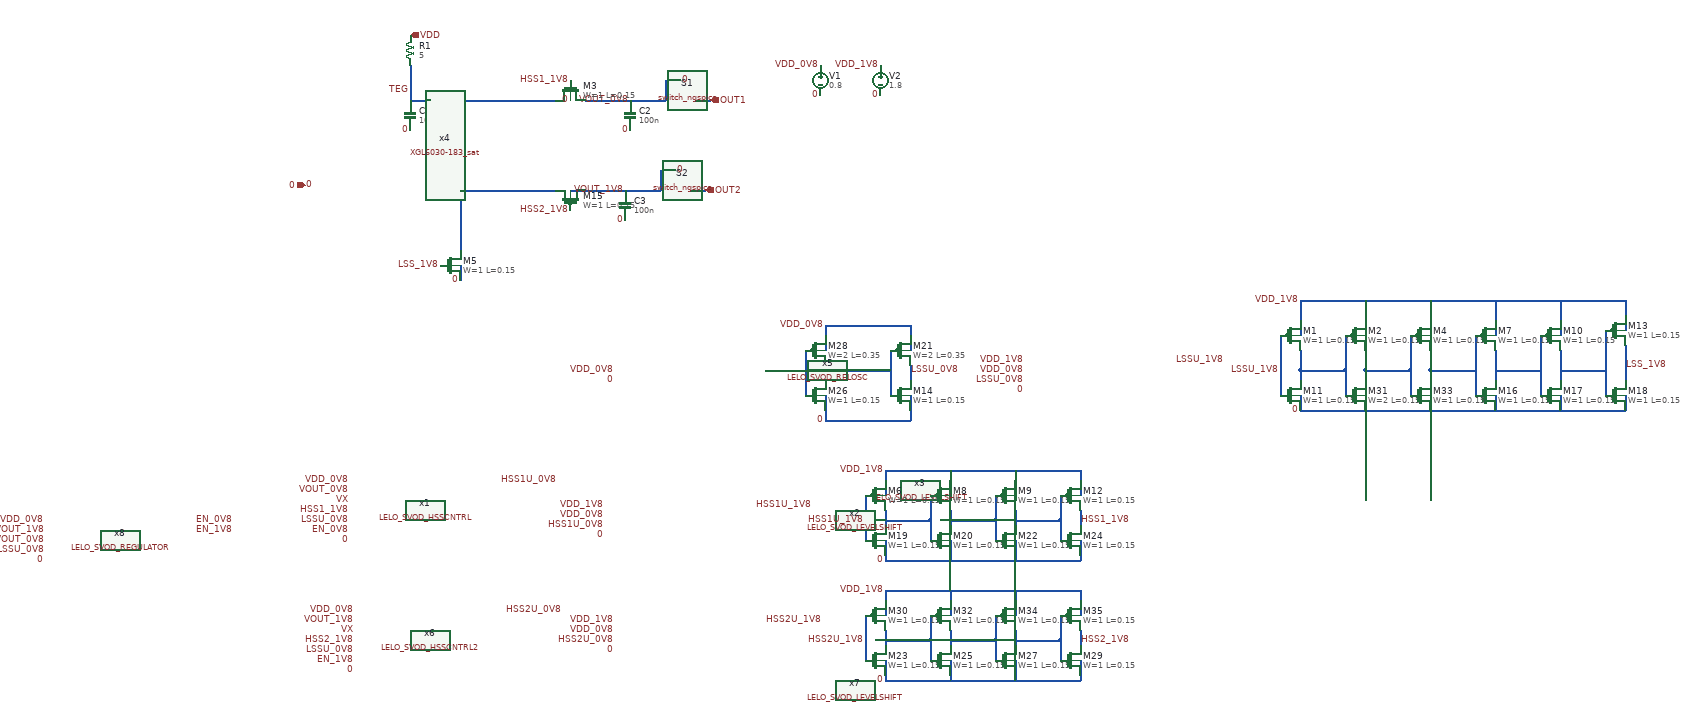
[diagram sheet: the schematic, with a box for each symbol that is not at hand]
v {xschem version=3.4.8RC file_version=1.2}
G {}
K {}
V {}
S {}
E {}
N -510 -330 -510 -260 {lab=TEG}
N -280 -260 -220 -260 {lab=VX}
N -410 -260 -280 -260 {lab=VX}
N -410 -260 -410 -100 {lab=VX}
N -490 -260 -470 -260 {lab=TEG}
N 1270 330 1270 360 {lab=0}
N 1660 240 1660 300 {lab=#net1}
N 1660 330 1660 360 {lab=0}
N 1620 210 1620 330 {lab=#net2}
N 1270 280 1360 280 {lab=#net3}
N -510 -260 -490 -260 {lab=TEG}
N 1790 240 1790 300 {lab=#net4}
N 1790 330 1790 360 {lab=0}
N 1750 210 1750 330 {lab=#net1}
N 1660 280 1750 280 {lab=#net1}
N 1920 230 1920 300 {lab=LSS_1V8}
N 1920 330 1920 360 {lab=0}
N 1880 200 1880 330 {lab=#net4}
N 1790 280 1880 280 {lab=#net4}
N -160 -260 -70 -260 {lab=VOUT_0V8}
N 1270 140 1850 140 {lab=VDD_1V8}
N 1660 140 1660 180 {lab=VDD_1V8}
N 1790 140 1790 180 {lab=VDD_1V8}
N 1920 140 1920 170 {lab=VDD_1V8}
N 1270 140 1270 180 {lab=VDD_1V8}
N 1270 240 1270 280 {lab=#net3}
N 1270 280 1270 300 {lab=#net3}
N 1230 210 1230 280 {lab=LSSU_1V8}
N 1230 280 1230 330 {lab=LSSU_1V8}
N 440 480 440 500 {lab=VDD_1V8}
N 570 480 570 500 {lab=VDD_1V8}
N 440 620 440 650 {lab=0}
N 570 620 570 650 {lab=0}
N 400 530 400 580 {lab=HSS1U_1V8}
N 400 580 400 620 {lab=HSS1U_1V8}
N 440 560 440 590 {lab=#net5}
N 440 650 440 660 {lab=0}
N 440 580 530 580 {lab=#net5}
N 530 530 530 580 {lab=#net5}
N 530 580 530 620 {lab=#net5}
N 570 560 570 590 {lab=#net6}
N 570 650 570 660 {lab=0}
N 700 480 700 500 {lab=VDD_1V8}
N 700 620 700 650 {lab=0}
N 570 580 660 580 {lab=#net6}
N 660 530 660 580 {lab=#net6}
N 660 580 660 620 {lab=#net6}
N 700 560 700 590 {lab=#net7}
N 700 650 700 660 {lab=0}
N 830 480 830 500 {lab=VDD_1V8}
N 830 620 830 650 {lab=0}
N 790 530 790 580 {lab=#net7}
N 790 580 790 620 {lab=#net7}
N 830 560 830 590 {lab=HSS1_1V8}
N 830 650 830 660 {lab=0}
N 1270 180 1270 210 {lab=VDD_1V8}
N 1660 180 1660 210 {lab=VDD_1V8}
N 1790 180 1790 210 {lab=VDD_1V8}
N 1920 170 1920 200 {lab=VDD_1V8}
N 440 500 440 530 {lab=VDD_1V8}
N 570 500 570 530 {lab=VDD_1V8}
N 700 500 700 530 {lab=VDD_1V8}
N 1400 330 1400 360 {lab=0}
N 1400 280 1490 280 {lab=#net8}
N 1400 140 1400 180 {lab=VDD_1V8}
N 1400 240 1400 280 {lab=#net8}
N 1400 280 1400 300 {lab=#net8}
N 1360 210 1360 280 {lab=#net3}
N 1360 280 1360 330 {lab=#net3}
N 1400 180 1400 210 {lab=VDD_1V8}
N 1530 330 1530 360 {lab=0}
N 1530 280 1620 280 {lab=#net2}
N 1530 140 1530 180 {lab=VDD_1V8}
N 1530 240 1530 280 {lab=#net2}
N 1530 280 1530 300 {lab=#net2}
N 1490 210 1490 280 {lab=#net8}
N 1490 280 1490 330 {lab=#net8}
N 1530 180 1530 210 {lab=VDD_1V8}
N 700 580 790 580 {lab=#net7}
N -410 -100 -410 -20 {lab=VX}
N -410 -20 -410 40 {lab=VX}
N -410 70 -410 100 {lab=0}
N 440 480 830 480 {lab=VDD_1V8}
N 830 500 830 530 {lab=VDD_1V8}
N 1850 140 1920 140 {lab=VDD_1V8}
N 1270 360 1920 360 {lab=0}
N 440 660 830 660 {lab=0}
N -70 -260 0 -260 {lab=VOUT_0V8}
N 0 -300 0 -260 {lab=VOUT_0V8}
N 0 -300 30 -300 {lab=VOUT_0V8}
N 60 -260 90 -260 {lab=OUT1}
N 450 240 450 330 {lab=#net9}
N 490 270 490 300 {lab=LSSU_0V8}
N 490 330 490 360 {lab=0}
N 490 210 490 240 {lab=VDD_0V8}
N 490 360 490 380 {lab=0}
N 490 190 490 210 {lab=VDD_0V8}
N 320 270 320 300 {lab=#net9}
N 280 240 280 330 {lab=#net10}
N 320 330 320 360 {lab=0}
N 320 210 320 240 {lab=VDD_0V8}
N 320 360 320 380 {lab=0}
N 320 190 320 210 {lab=VDD_0V8}
N 320 190 490 190 {lab=VDD_0V8}
N 320 380 490 380 {lab=0}
N 200 280 280 280 {lab=#net10}
N 320 280 450 280 {lab=#net9}
N -410 -80 -220 -80 {lab=VX}
N -190 -80 -160 -80 {lab=VOUT_1V8}
N -160 -80 -80 -80 {lab=VOUT_1V8}
N -80 -80 -10 -80 {lab=VOUT_1V8}
N 440 720 440 740 {lab=VDD_1V8}
N 570 720 570 740 {lab=VDD_1V8}
N 440 860 440 890 {lab=0}
N 570 860 570 890 {lab=0}
N 400 770 400 820 {lab=HSS2U_1V8}
N 400 820 400 860 {lab=HSS2U_1V8}
N 440 800 440 830 {lab=#net11}
N 440 890 440 900 {lab=0}
N 440 820 530 820 {lab=#net11}
N 530 770 530 820 {lab=#net11}
N 530 820 530 860 {lab=#net11}
N 570 800 570 830 {lab=#net12}
N 570 890 570 900 {lab=0}
N 700 720 700 740 {lab=VDD_1V8}
N 700 860 700 890 {lab=0}
N 570 820 660 820 {lab=#net12}
N 660 770 660 820 {lab=#net12}
N 660 820 660 860 {lab=#net12}
N 700 800 700 830 {lab=#net13}
N 700 890 700 900 {lab=0}
N 830 720 830 740 {lab=VDD_1V8}
N 830 860 830 890 {lab=0}
N 790 770 790 820 {lab=#net13}
N 790 820 790 860 {lab=#net13}
N 830 800 830 830 {lab=HSS2_1V8}
N 830 890 830 900 {lab=0}
N 440 740 440 770 {lab=VDD_1V8}
N 570 740 570 770 {lab=VDD_1V8}
N 700 740 700 770 {lab=VDD_1V8}
N 700 820 790 820 {lab=#net13}
N 440 720 830 720 {lab=VDD_1V8}
N 830 740 830 770 {lab=VDD_1V8}
N 440 900 830 900 {lab=0}
N -10 -120 -10 -80 {lab=VOUT_1V8}
N -10 -120 20 -120 {lab=VOUT_1V8}
N 50 -80 80 -80 {lab=VOUT_1V8}
C {devices/ipin.sym} -510 -390 0 1 {name=p2 lab=VDD}
C {devices/lab_pin.sym} -410 -260 3 1 {name=p3 sig_type=std_logic lab=VX}
C {devices/res.sym} -510 -360 0 1 {name=R1
value=5
footprint=1206
device=resistor
m=1}
C {devices/lab_pin.sym} 440 660 3 0 {name=p77 sig_type=std_logic lab=0}
C {devices/lab_pin.sym} -100 300 3 0 {name=p13 sig_type=std_logic lab=0}
C {devices/lab_pin.sym} 1920 270 0 1 {name=p30 sig_type=std_logic lab=LSS_1V8}
C {devices/capa.sym} -510 -230 0 1 {name=C1
m=1
value=100u
footprint=1206
device="ceramic capacitor"}
C {devices/lab_pin.sym} -510 -200 3 0 {name=p7 sig_type=std_logic lab=0}
C {sky130_fd_pr/nfet_01v8_lvt.sym} -430 70 0 0 {name=M5
W=1
L=0.15
nf=1
mult=15804
ad="expr('int((@nf + 1)/2) * @W / @nf * 0.29')"
pd="expr('2*int((@nf + 1)/2) * (@W / @nf + 0.29)')"
as="expr('int((@nf + 2)/2) * @W / @nf * 0.29')"
ps="expr('2*int((@nf + 2)/2) * (@W / @nf + 0.29)')"
nrd="expr('0.29 / @W ')" nrs="expr('0.29 / @W ')"
sa=0 sb=0 sd=0
model=nfet_01v8_lvt
spiceprefix=X
}
C {devices/lab_pin.sym} -510 -280 2 1 {name=p93 sig_type=std_logic lab=TEG}
C {devices/capa.sym} -70 -230 0 1 {name=C2
m=1
value=100n
footprint=1206
device="ceramic capacitor"}
C {devices/lab_pin.sym} -70 -200 3 0 {name=p1 sig_type=std_logic lab=0}
C {devices/lab_pin.sym} -70 -260 1 0 {name=p35 sig_type=std_logic lab=VOUT_0V8}
C {sky130_fd_pr/nfet_01v8.sym} 1250 330 0 0 {name=M11
W=1
L=0.15
nf=1 
mult=1
ad="expr('int((@nf + 1)/2) * @W / @nf * 0.29')"
pd="expr('2*int((@nf + 1)/2) * (@W / @nf + 0.29)')"
as="expr('int((@nf + 2)/2) * @W / @nf * 0.29')"
ps="expr('2*int((@nf + 2)/2) * (@W / @nf + 0.29)')"
nrd="expr('0.29 / @W ')" nrs="expr('0.29 / @W ')"
sa=0 sb=0 sd=0
model=nfet_01v8
spiceprefix=X
}
C {sky130_fd_pr/nfet_01v8.sym} 1640 330 0 0 {name=M16
W=1
L=0.15
nf=1 
mult=27
ad="expr('int((@nf + 1)/2) * @W / @nf * 0.29')"
pd="expr('2*int((@nf + 1)/2) * (@W / @nf + 0.29)')"
as="expr('int((@nf + 2)/2) * @W / @nf * 0.29')"
ps="expr('2*int((@nf + 2)/2) * (@W / @nf + 0.29)')"
nrd="expr('0.29 / @W ')" nrs="expr('0.29 / @W ')"
sa=0 sb=0 sd=0
model=nfet_01v8
spiceprefix=X
}
C {sky130_fd_pr/nfet_01v8.sym} 1770 330 0 0 {name=M17
W=1
L=0.15
nf=1 
mult=81
ad="expr('int((@nf + 1)/2) * @W / @nf * 0.29')"
pd="expr('2*int((@nf + 1)/2) * (@W / @nf + 0.29)')"
as="expr('int((@nf + 2)/2) * @W / @nf * 0.29')"
ps="expr('2*int((@nf + 2)/2) * (@W / @nf + 0.29)')"
nrd="expr('0.29 / @W ')" nrs="expr('0.29 / @W ')"
sa=0 sb=0 sd=0
model=nfet_01v8
spiceprefix=X
}
C {sky130_fd_pr/nfet_01v8.sym} 1900 330 0 0 {name=M18
W=1
L=0.15
nf=1 
mult=243
ad="expr('int((@nf + 1)/2) * @W / @nf * 0.29')"
pd="expr('2*int((@nf + 1)/2) * (@W / @nf + 0.29)')"
as="expr('int((@nf + 2)/2) * @W / @nf * 0.29')"
ps="expr('2*int((@nf + 2)/2) * (@W / @nf + 0.29)')"
nrd="expr('0.29 / @W ')" nrs="expr('0.29 / @W ')"
sa=0 sb=0 sd=0
model=nfet_01v8
spiceprefix=X
}
C {sky130_fd_pr/nfet_01v8.sym} 420 620 0 0 {name=M19
W=1
L=0.15
nf=1 
mult=1
ad="expr('int((@nf + 1)/2) * @W / @nf * 0.29')"
pd="expr('2*int((@nf + 1)/2) * (@W / @nf + 0.29)')"
as="expr('int((@nf + 2)/2) * @W / @nf * 0.29')"
ps="expr('2*int((@nf + 2)/2) * (@W / @nf + 0.29)')"
nrd="expr('0.29 / @W ')" nrs="expr('0.29 / @W ')"
sa=0 sb=0 sd=0
model=nfet_01v8
spiceprefix=X
}
C {sky130_fd_pr/nfet_01v8.sym} 550 620 0 0 {name=M20
W=1
L=0.15
nf=1 
mult=3
ad="expr('int((@nf + 1)/2) * @W / @nf * 0.29')"
pd="expr('2*int((@nf + 1)/2) * (@W / @nf + 0.29)')"
as="expr('int((@nf + 2)/2) * @W / @nf * 0.29')"
ps="expr('2*int((@nf + 2)/2) * (@W / @nf + 0.29)')"
nrd="expr('0.29 / @W ')" nrs="expr('0.29 / @W ')"
sa=0 sb=0 sd=0
model=nfet_01v8
spiceprefix=X
}
C {sky130_fd_pr/nfet_01v8.sym} 680 620 0 0 {name=M22
W=1
L=0.15
nf=1 
mult=9
ad="expr('int((@nf + 1)/2) * @W / @nf * 0.29')"
pd="expr('2*int((@nf + 1)/2) * (@W / @nf + 0.29)')"
as="expr('int((@nf + 2)/2) * @W / @nf * 0.29')"
ps="expr('2*int((@nf + 2)/2) * (@W / @nf + 0.29)')"
nrd="expr('0.29 / @W ')" nrs="expr('0.29 / @W ')"
sa=0 sb=0 sd=0
model=nfet_01v8
spiceprefix=X
}
C {sky130_fd_pr/nfet_01v8.sym} 810 620 0 0 {name=M24
W=1
L=0.15
nf=1 
mult=27
ad="expr('int((@nf + 1)/2) * @W / @nf * 0.29')"
pd="expr('2*int((@nf + 1)/2) * (@W / @nf + 0.29)')"
as="expr('int((@nf + 2)/2) * @W / @nf * 0.29')"
ps="expr('2*int((@nf + 2)/2) * (@W / @nf + 0.29)')"
nrd="expr('0.29 / @W ')" nrs="expr('0.29 / @W ')"
sa=0 sb=0 sd=0
model=nfet_01v8
spiceprefix=X
}
C {sky130_fd_pr/nfet_01v8.sym} 1380 330 0 0 {name=M31
W=2
L=0.15
nf=1 
mult=3
ad="expr('int((@nf + 1)/2) * @W / @nf * 0.29')"
pd="expr('2*int((@nf + 1)/2) * (@W / @nf + 0.29)')"
as="expr('int((@nf + 2)/2) * @W / @nf * 0.29')"
ps="expr('2*int((@nf + 2)/2) * (@W / @nf + 0.29)')"
nrd="expr('0.29 / @W ')" nrs="expr('0.29 / @W ')"
sa=0 sb=0 sd=0
model=nfet_01v8
spiceprefix=X
}
C {sky130_fd_pr/nfet_01v8.sym} 1510 330 0 0 {name=M33
W=1
L=0.15
nf=1 
mult=9
ad="expr('int((@nf + 1)/2) * @W / @nf * 0.29')"
pd="expr('2*int((@nf + 1)/2) * (@W / @nf + 0.29)')"
as="expr('int((@nf + 2)/2) * @W / @nf * 0.29')"
ps="expr('2*int((@nf + 2)/2) * (@W / @nf + 0.29)')"
nrd="expr('0.29 / @W ')" nrs="expr('0.29 / @W ')"
sa=0 sb=0 sd=0
model=nfet_01v8
spiceprefix=X
}
C {devices/lab_pin.sym} -190 -300 1 0 {name=p101 sig_type=std_logic lab=HSS1_1V8}
C {sky130_fd_pr/nfet_01v8_lvt.sym} -190 -280 1 0 {name=M3
W=1
L=0.15
nf=1
mult=3244
ad="expr('int((@nf + 1)/2) * @W / @nf * 0.29')"
pd="expr('2*int((@nf + 1)/2) * (@W / @nf + 0.29)')"
as="expr('int((@nf + 2)/2) * @W / @nf * 0.29')"
ps="expr('2*int((@nf + 2)/2) * (@W / @nf + 0.29)')"
nrd="expr('0.29 / @W ')" nrs="expr('0.29 / @W ')"
sa=0 sb=0 sd=0
model=nfet_01v8_lvt
spiceprefix=X
}
C {devices/lab_pin.sym} 490 280 0 1 {name=p10 sig_type=std_logic lab=LSSU_0V8}
C {devices/lab_pin.sym} -410 100 3 0 {name=p12 sig_type=std_logic lab=0}
C {LELO_SVOD_SKY130A/LELO_SVOD_HSSCNTRL.sym} -480 560 0 0 {name=x1}
C {devices/lab_pin.sym} -630 620 0 0 {name=p19 sig_type=std_logic lab=0}
C {devices/lab_pin.sym} -330 500 2 0 {name=p22 sig_type=std_logic lab=HSS1U_0V8}
C {devices/lab_pin.sym} -630 540 2 1 {name=p26 sig_type=std_logic lab=VX}
C {devices/lab_pin.sym} -630 520 0 0 {name=p27 sig_type=std_logic lab=VOUT_0V8}
C {devices/lab_pin.sym} -190 -260 3 0 {name=p6 sig_type=std_logic lab=0}
C {LELO_SVOD_SKY130A/LELO_SVOD_LEVELSHIFT.sym} 30 580 0 0 {name=x2}
C {LELO_SVOD_SKY130A/LELO_SVOD_LEVELSHIFT.sym} 870 290 0 0 {name=x3}
C {devices/lab_pin.sym} 180 550 2 0 {name=p8 sig_type=std_logic lab=HSS1U_1V8}
C {devices/lab_pin.sym} -120 610 0 0 {name=p20 sig_type=std_logic lab=0}
C {devices/lab_pin.sym} 1020 260 0 1 {name=p23 sig_type=std_logic lab=LSSU_1V8}
C {devices/lab_pin.sym} 720 320 0 0 {name=p24 sig_type=std_logic lab=0}
C {sky130_fd_pr/pfet_01v8_hvt.sym} 420 530 0 0 {name=M6
W=1
L=0.15
nf=1
mult=1
ad="expr('int((@nf + 1)/2) * @W / @nf * 0.29')"
pd="expr('2*int((@nf + 1)/2) * (@W / @nf + 0.29)')"
as="expr('int((@nf + 2)/2) * @W / @nf * 0.29')"
ps="expr('2*int((@nf + 2)/2) * (@W / @nf + 0.29)')"
nrd="expr('0.29 / @W ')" nrs="expr('0.29 / @W ')"
sa=0 sb=0 sd=0
model=pfet_01v8_hvt
spiceprefix=X
}
C {sky130_fd_pr/pfet_01v8_hvt.sym} 550 530 0 0 {name=M8
W=1
L=0.15
nf=1
mult=3
ad="expr('int((@nf + 1)/2) * @W / @nf * 0.29')"
pd="expr('2*int((@nf + 1)/2) * (@W / @nf + 0.29)')"
as="expr('int((@nf + 2)/2) * @W / @nf * 0.29')"
ps="expr('2*int((@nf + 2)/2) * (@W / @nf + 0.29)')"
nrd="expr('0.29 / @W ')" nrs="expr('0.29 / @W ')"
sa=0 sb=0 sd=0
model=pfet_01v8_hvt
spiceprefix=X
}
C {sky130_fd_pr/pfet_01v8_hvt.sym} 680 530 0 0 {name=M9
W=1
L=0.15
nf=1
mult=9
ad="expr('int((@nf + 1)/2) * @W / @nf * 0.29')"
pd="expr('2*int((@nf + 1)/2) * (@W / @nf + 0.29)')"
as="expr('int((@nf + 2)/2) * @W / @nf * 0.29')"
ps="expr('2*int((@nf + 2)/2) * (@W / @nf + 0.29)')"
nrd="expr('0.29 / @W ')" nrs="expr('0.29 / @W ')"
sa=0 sb=0 sd=0
model=pfet_01v8_hvt
spiceprefix=X
}
C {sky130_fd_pr/pfet_01v8_hvt.sym} 810 530 0 0 {name=M12
W=1
L=0.15
nf=1
mult=27
ad="expr('int((@nf + 1)/2) * @W / @nf * 0.29')"
pd="expr('2*int((@nf + 1)/2) * (@W / @nf + 0.29)')"
as="expr('int((@nf + 2)/2) * @W / @nf * 0.29')"
ps="expr('2*int((@nf + 2)/2) * (@W / @nf + 0.29)')"
nrd="expr('0.29 / @W ')" nrs="expr('0.29 / @W ')"
sa=0 sb=0 sd=0
model=pfet_01v8_hvt
spiceprefix=X
}
C {sky130_fd_pr/pfet_01v8_hvt.sym} 1250 210 0 0 {name=M1
W=1
L=0.15
nf=1
mult=1
ad="expr('int((@nf + 1)/2) * @W / @nf * 0.29')"
pd="expr('2*int((@nf + 1)/2) * (@W / @nf + 0.29)')"
as="expr('int((@nf + 2)/2) * @W / @nf * 0.29')"
ps="expr('2*int((@nf + 2)/2) * (@W / @nf + 0.29)')"
nrd="expr('0.29 / @W ')" nrs="expr('0.29 / @W ')"
sa=0 sb=0 sd=0
model=pfet_01v8_hvt
spiceprefix=X
}
C {sky130_fd_pr/pfet_01v8_hvt.sym} 1380 210 0 0 {name=M2
W=1
L=0.15
nf=1
mult=3
ad="expr('int((@nf + 1)/2) * @W / @nf * 0.29')"
pd="expr('2*int((@nf + 1)/2) * (@W / @nf + 0.29)')"
as="expr('int((@nf + 2)/2) * @W / @nf * 0.29')"
ps="expr('2*int((@nf + 2)/2) * (@W / @nf + 0.29)')"
nrd="expr('0.29 / @W ')" nrs="expr('0.29 / @W ')"
sa=0 sb=0 sd=0
model=pfet_01v8_hvt
spiceprefix=X
}
C {sky130_fd_pr/pfet_01v8_hvt.sym} 1510 210 0 0 {name=M4
W=1
L=0.15
nf=1
mult=9
ad="expr('int((@nf + 1)/2) * @W / @nf * 0.29')"
pd="expr('2*int((@nf + 1)/2) * (@W / @nf + 0.29)')"
as="expr('int((@nf + 2)/2) * @W / @nf * 0.29')"
ps="expr('2*int((@nf + 2)/2) * (@W / @nf + 0.29)')"
nrd="expr('0.29 / @W ')" nrs="expr('0.29 / @W ')"
sa=0 sb=0 sd=0
model=pfet_01v8_hvt
spiceprefix=X
}
C {sky130_fd_pr/pfet_01v8_hvt.sym} 1640 210 0 0 {name=M7
W=1
L=0.15
nf=1
mult=27
ad="expr('int((@nf + 1)/2) * @W / @nf * 0.29')"
pd="expr('2*int((@nf + 1)/2) * (@W / @nf + 0.29)')"
as="expr('int((@nf + 2)/2) * @W / @nf * 0.29')"
ps="expr('2*int((@nf + 2)/2) * (@W / @nf + 0.29)')"
nrd="expr('0.29 / @W ')" nrs="expr('0.29 / @W ')"
sa=0 sb=0 sd=0
model=pfet_01v8_hvt
spiceprefix=X
}
C {sky130_fd_pr/pfet_01v8_hvt.sym} 1770 210 0 0 {name=M10
W=1
L=0.15
nf=1
mult=81
ad="expr('int((@nf + 1)/2) * @W / @nf * 0.29')"
pd="expr('2*int((@nf + 1)/2) * (@W / @nf + 0.29)')"
as="expr('int((@nf + 2)/2) * @W / @nf * 0.29')"
ps="expr('2*int((@nf + 2)/2) * (@W / @nf + 0.29)')"
nrd="expr('0.29 / @W ')" nrs="expr('0.29 / @W ')"
sa=0 sb=0 sd=0
model=pfet_01v8_hvt
spiceprefix=X
}
C {sky130_fd_pr/pfet_01v8_hvt.sym} 1900 200 0 0 {name=M13
W=1
L=0.15
nf=1
mult=243
ad="expr('int((@nf + 1)/2) * @W / @nf * 0.29')"
pd="expr('2*int((@nf + 1)/2) * (@W / @nf + 0.29)')"
as="expr('int((@nf + 2)/2) * @W / @nf * 0.29')"
ps="expr('2*int((@nf + 2)/2) * (@W / @nf + 0.29)')"
nrd="expr('0.29 / @W ')" nrs="expr('0.29 / @W ')"
sa=0 sb=0 sd=0
model=pfet_01v8_hvt
spiceprefix=X
}
C {devices/lab_pin.sym} -120 590 2 1 {name=p5 sig_type=std_logic lab=HSS1U_0V8}
C {devices/lab_pin.sym} 400 580 2 1 {name=p9 sig_type=std_logic lab=HSS1U_1V8}
C {devices/lab_pin.sym} 1270 360 3 0 {name=p4 sig_type=std_logic lab=0}
C {devices/vsource.sym} 310 -300 0 0 {name=V1 value=0.8 savecurrent=false}
C {devices/vsource.sym} 430 -300 0 0 {name=V2 value=1.8 savecurrent=false}
C {devices/lab_pin.sym} 310 -270 3 0 {name=p11 sig_type=std_logic lab=0}
C {devices/lab_pin.sym} 430 -270 3 0 {name=p14 sig_type=std_logic lab=0}
C {devices/lab_pin.sym} 310 -330 1 0 {name=p15 sig_type=std_logic lab=VDD_0V8}
C {devices/lab_pin.sym} 430 -330 1 0 {name=p16 sig_type=std_logic lab=VDD_1V8}
C {devices/lab_pin.sym} -100 280 0 0 {name=p17 sig_type=std_logic lab=VDD_0V8}
C {devices/lab_pin.sym} -630 500 0 0 {name=p21 sig_type=std_logic lab=VDD_0V8}
C {devices/lab_pin.sym} -120 570 0 0 {name=p28 sig_type=std_logic lab=VDD_0V8}
C {devices/lab_pin.sym} 720 280 0 0 {name=p29 sig_type=std_logic lab=VDD_0V8}
C {devices/lab_pin.sym} -120 550 0 0 {name=p31 sig_type=std_logic lab=VDD_1V8}
C {devices/lab_pin.sym} 720 260 0 0 {name=p32 sig_type=std_logic lab=VDD_1V8}
C {devices/lab_pin.sym} 440 480 0 0 {name=p33 sig_type=std_logic lab=VDD_1V8}
C {devices/lab_pin.sym} 1270 140 0 0 {name=p34 sig_type=std_logic lab=VDD_1V8}
C {devices/lab_pin.sym} -450 70 0 0 {name=p36 sig_type=std_logic lab=LSS_1V8}
C {devices/lab_pin.sym} 720 300 0 0 {name=p37 sig_type=std_logic lab=LSSU_0V8}
C {devices/lab_pin.sym} 1230 280 0 0 {name=p38 sig_type=std_logic lab=LSSU_1V8}
C {devices/lab_pin.sym} 830 580 2 0 {name=p39 sig_type=std_logic lab=HSS1_1V8}
C {devices/ipin.sym} -720 -90 0 0 {name=p40 lab=0}
C {devices/lab_pin.sym} -720 -90 2 0 {name=p41 sig_type=std_logic lab=0}
C {devices/switch_ngspice.sym} 30 -260 3 1 {name=S1 model=SW1
device_model=".MODEL SW1 SW 
+ VT=0.7 VH=0.001
+ RON=0.001 ROFF=10G "}
C {devices/lab_pin.sym} 50 -300 1 0 {name=p42 sig_type=std_logic lab=0}
C {devices/lab_pin.sym} -630 580 0 0 {name=p25 sig_type=std_logic lab=LSSU_0V8}
C {sky130_fd_pr/nfet_01v8_lvt.sym} 470 330 0 0 {name=M14
W=1
L=0.15
nf=1
mult=2
ad="expr('int((@nf + 1)/2) * @W / @nf * 0.29')"
pd="expr('2*int((@nf + 1)/2) * (@W / @nf + 0.29)')"
as="expr('int((@nf + 2)/2) * @W / @nf * 0.29')"
ps="expr('2*int((@nf + 2)/2) * (@W / @nf + 0.29)')"
nrd="expr('0.29 / @W ')" nrs="expr('0.29 / @W ')"
sa=0 sb=0 sd=0
model=nfet_01v8_lvt
spiceprefix=X
}
C {sky130_fd_pr/pfet_01v8_lvt.sym} 470 240 0 0 {name=M21
W=2
L=0.35
nf=1
mult=4
ad="expr('int((@nf + 1)/2) * @W / @nf * 0.29')"
pd="expr('2*int((@nf + 1)/2) * (@W / @nf + 0.29)')"
as="expr('int((@nf + 2)/2) * @W / @nf * 0.29')"
ps="expr('2*int((@nf + 2)/2) * (@W / @nf + 0.29)')"
nrd="expr('0.29 / @W ')" nrs="expr('0.29 / @W ')"
sa=0 sb=0 sd=0
model=pfet_01v8_lvt
spiceprefix=X
}
C {devices/lab_pin.sym} -630 560 0 0 {name=p49 sig_type=std_logic lab=HSS1_1V8}
C {sky130_fd_pr/nfet_01v8_lvt.sym} 300 330 0 0 {name=M26
W=1
L=0.15
nf=1
mult=1
ad="expr('int((@nf + 1)/2) * @W / @nf * 0.29')"
pd="expr('2*int((@nf + 1)/2) * (@W / @nf + 0.29)')"
as="expr('int((@nf + 2)/2) * @W / @nf * 0.29')"
ps="expr('2*int((@nf + 2)/2) * (@W / @nf + 0.29)')"
nrd="expr('0.29 / @W ')" nrs="expr('0.29 / @W ')"
sa=0 sb=0 sd=0
model=nfet_01v8_lvt
spiceprefix=X
}
C {sky130_fd_pr/pfet_01v8_lvt.sym} 300 240 0 0 {name=M28
W=2
L=0.35
nf=1
mult=1
ad="expr('int((@nf + 1)/2) * @W / @nf * 0.29')"
pd="expr('2*int((@nf + 1)/2) * (@W / @nf + 0.29)')"
as="expr('int((@nf + 2)/2) * @W / @nf * 0.29')"
ps="expr('2*int((@nf + 2)/2) * (@W / @nf + 0.29)')"
nrd="expr('0.29 / @W ')" nrs="expr('0.29 / @W ')"
sa=0 sb=0 sd=0
model=pfet_01v8_lvt
spiceprefix=X
}
C {devices/lab_pin.sym} 320 190 1 0 {name=p51 sig_type=std_logic lab=VDD_0V8}
C {devices/lab_pin.sym} 320 380 3 0 {name=p52 sig_type=std_logic lab=0}
C {LELO_SVOD_SKY130A/XGL6030-183_sat.sym} -440 -260 1 0 {name=x4}
C {LELO_SVOD_SKY130A/LELO_SVOD_RELOSC.sym} 50 290 0 0 {name=x5}
C {sky130_fd_pr/pfet_01v8.sym} -190 -60 1 1 {name=M15
W=1
L=0.15
nf=1
mult=481
ad="expr('int((@nf + 1)/2) * @W / @nf * 0.29')"
pd="expr('2*int((@nf + 1)/2) * (@W / @nf + 0.29)')"
as="expr('int((@nf + 2)/2) * @W / @nf * 0.29')"
ps="expr('2*int((@nf + 2)/2) * (@W / @nf + 0.29)')"
nrd="expr('0.29 / @W ')" nrs="expr('0.29 / @W ')"
sa=0 sb=0 sd=0
model=pfet_01v8
spiceprefix=X
}
C {devices/capa.sym} -80 -50 0 1 {name=C3
m=1
value=100n
footprint=1206
device="ceramic capacitor"}
C {devices/lab_pin.sym} -80 -20 3 0 {name=p44 sig_type=std_logic lab=0}
C {devices/lab_pin.sym} -80 -80 1 0 {name=p45 sig_type=std_logic lab=VOUT_1V8}
C {devices/opin.sym} 80 -80 0 0 {name=p47 lab=OUT2}
C {LELO_SVOD_SKY130A/LELO_SVOD_HSSCNTRL2.sym} -470 820 0 0 {name=x6}
C {devices/lab_pin.sym} -620 800 2 1 {name=p48 sig_type=std_logic lab=VX}
C {devices/lab_pin.sym} -620 760 0 0 {name=p50 sig_type=std_logic lab=VDD_0V8}
C {devices/lab_pin.sym} -620 780 0 0 {name=p53 sig_type=std_logic lab=VOUT_1V8}
C {devices/lab_pin.sym} -620 840 0 0 {name=p54 sig_type=std_logic lab=LSSU_0V8}
C {devices/lab_pin.sym} -620 880 0 0 {name=p56 sig_type=std_logic lab=0}
C {devices/lab_pin.sym} -320 760 2 0 {name=p57 sig_type=std_logic lab=HSS2U_0V8}
C {LELO_SVOD_SKY130A/LELO_SVOD_LEVELSHIFT.sym} 50 810 0 0 {name=x7}
C {devices/lab_pin.sym} 200 780 2 0 {name=p58 sig_type=std_logic lab=HSS2U_1V8}
C {devices/lab_pin.sym} -100 840 0 0 {name=p59 sig_type=std_logic lab=0}
C {devices/lab_pin.sym} -100 800 0 0 {name=p61 sig_type=std_logic lab=VDD_0V8}
C {devices/lab_pin.sym} -100 780 0 0 {name=p62 sig_type=std_logic lab=VDD_1V8}
C {devices/lab_pin.sym} -100 820 2 1 {name=p60 sig_type=std_logic lab=HSS2U_0V8}
C {devices/lab_pin.sym} 440 900 3 0 {name=p63 sig_type=std_logic lab=0}
C {sky130_fd_pr/nfet_01v8.sym} 420 860 0 0 {name=M23
W=1
L=0.15
nf=1 
mult=1
ad="expr('int((@nf + 1)/2) * @W / @nf * 0.29')"
pd="expr('2*int((@nf + 1)/2) * (@W / @nf + 0.29)')"
as="expr('int((@nf + 2)/2) * @W / @nf * 0.29')"
ps="expr('2*int((@nf + 2)/2) * (@W / @nf + 0.29)')"
nrd="expr('0.29 / @W ')" nrs="expr('0.29 / @W ')"
sa=0 sb=0 sd=0
model=nfet_01v8
spiceprefix=X
}
C {sky130_fd_pr/nfet_01v8.sym} 550 860 0 0 {name=M25
W=1
L=0.15
nf=1 
mult=3
ad="expr('int((@nf + 1)/2) * @W / @nf * 0.29')"
pd="expr('2*int((@nf + 1)/2) * (@W / @nf + 0.29)')"
as="expr('int((@nf + 2)/2) * @W / @nf * 0.29')"
ps="expr('2*int((@nf + 2)/2) * (@W / @nf + 0.29)')"
nrd="expr('0.29 / @W ')" nrs="expr('0.29 / @W ')"
sa=0 sb=0 sd=0
model=nfet_01v8
spiceprefix=X
}
C {sky130_fd_pr/nfet_01v8.sym} 680 860 0 0 {name=M27
W=1
L=0.15
nf=1 
mult=9
ad="expr('int((@nf + 1)/2) * @W / @nf * 0.29')"
pd="expr('2*int((@nf + 1)/2) * (@W / @nf + 0.29)')"
as="expr('int((@nf + 2)/2) * @W / @nf * 0.29')"
ps="expr('2*int((@nf + 2)/2) * (@W / @nf + 0.29)')"
nrd="expr('0.29 / @W ')" nrs="expr('0.29 / @W ')"
sa=0 sb=0 sd=0
model=nfet_01v8
spiceprefix=X
}
C {sky130_fd_pr/nfet_01v8.sym} 810 860 0 0 {name=M29
W=1
L=0.15
nf=1 
mult=27
ad="expr('int((@nf + 1)/2) * @W / @nf * 0.29')"
pd="expr('2*int((@nf + 1)/2) * (@W / @nf + 0.29)')"
as="expr('int((@nf + 2)/2) * @W / @nf * 0.29')"
ps="expr('2*int((@nf + 2)/2) * (@W / @nf + 0.29)')"
nrd="expr('0.29 / @W ')" nrs="expr('0.29 / @W ')"
sa=0 sb=0 sd=0
model=nfet_01v8
spiceprefix=X
}
C {sky130_fd_pr/pfet_01v8_hvt.sym} 420 770 0 0 {name=M30
W=1
L=0.15
nf=1
mult=1
ad="expr('int((@nf + 1)/2) * @W / @nf * 0.29')"
pd="expr('2*int((@nf + 1)/2) * (@W / @nf + 0.29)')"
as="expr('int((@nf + 2)/2) * @W / @nf * 0.29')"
ps="expr('2*int((@nf + 2)/2) * (@W / @nf + 0.29)')"
nrd="expr('0.29 / @W ')" nrs="expr('0.29 / @W ')"
sa=0 sb=0 sd=0
model=pfet_01v8_hvt
spiceprefix=X
}
C {sky130_fd_pr/pfet_01v8_hvt.sym} 550 770 0 0 {name=M32
W=1
L=0.15
nf=1
mult=3
ad="expr('int((@nf + 1)/2) * @W / @nf * 0.29')"
pd="expr('2*int((@nf + 1)/2) * (@W / @nf + 0.29)')"
as="expr('int((@nf + 2)/2) * @W / @nf * 0.29')"
ps="expr('2*int((@nf + 2)/2) * (@W / @nf + 0.29)')"
nrd="expr('0.29 / @W ')" nrs="expr('0.29 / @W ')"
sa=0 sb=0 sd=0
model=pfet_01v8_hvt
spiceprefix=X
}
C {sky130_fd_pr/pfet_01v8_hvt.sym} 680 770 0 0 {name=M34
W=1
L=0.15
nf=1
mult=9
ad="expr('int((@nf + 1)/2) * @W / @nf * 0.29')"
pd="expr('2*int((@nf + 1)/2) * (@W / @nf + 0.29)')"
as="expr('int((@nf + 2)/2) * @W / @nf * 0.29')"
ps="expr('2*int((@nf + 2)/2) * (@W / @nf + 0.29)')"
nrd="expr('0.29 / @W ')" nrs="expr('0.29 / @W ')"
sa=0 sb=0 sd=0
model=pfet_01v8_hvt
spiceprefix=X
}
C {sky130_fd_pr/pfet_01v8_hvt.sym} 810 770 0 0 {name=M35
W=1
L=0.15
nf=1
mult=27
ad="expr('int((@nf + 1)/2) * @W / @nf * 0.29')"
pd="expr('2*int((@nf + 1)/2) * (@W / @nf + 0.29)')"
as="expr('int((@nf + 2)/2) * @W / @nf * 0.29')"
ps="expr('2*int((@nf + 2)/2) * (@W / @nf + 0.29)')"
nrd="expr('0.29 / @W ')" nrs="expr('0.29 / @W ')"
sa=0 sb=0 sd=0
model=pfet_01v8_hvt
spiceprefix=X
}
C {devices/lab_pin.sym} 440 720 0 0 {name=p65 sig_type=std_logic lab=VDD_1V8}
C {devices/lab_pin.sym} 830 820 2 0 {name=p66 sig_type=std_logic lab=HSS2_1V8}
C {devices/lab_pin.sym} 400 820 2 1 {name=p64 sig_type=std_logic lab=HSS2U_1V8}
C {devices/lab_pin.sym} -620 820 2 1 {name=p67 sig_type=std_logic lab=HSS2_1V8}
C {devices/lab_pin.sym} -190 -40 1 1 {name=p68 sig_type=std_logic lab=HSS2_1V8}
C {devices/opin.sym} 90 -260 0 0 {name=p43 lab=OUT1}
C {LELO_SVOD_SKY130A/LELO_SVOD_REGULATOR.sym} -1090 620 0 0 {name=x8}
C {devices/lab_pin.sym} -940 580 0 1 {name=p18 sig_type=std_logic lab=EN_0V8}
C {devices/lab_pin.sym} -630 600 0 0 {name=p55 sig_type=std_logic lab=EN_0V8}
C {devices/lab_pin.sym} -940 600 0 1 {name=p69 sig_type=std_logic lab=EN_1V8}
C {devices/lab_pin.sym} -620 860 0 0 {name=p70 sig_type=std_logic lab=EN_1V8}
C {devices/lab_pin.sym} -1240 620 0 0 {name=p71 sig_type=std_logic lab=VOUT_0V8}
C {devices/lab_pin.sym} -1240 600 0 0 {name=p72 sig_type=std_logic lab=VOUT_1V8}
C {devices/lab_pin.sym} -1240 660 3 0 {name=p73 sig_type=std_logic lab=0}
C {devices/lab_pin.sym} -1240 640 0 0 {name=p74 sig_type=std_logic lab=LSSU_0V8}
C {devices/lab_pin.sym} -1240 580 0 0 {name=p46 sig_type=std_logic lab=VDD_0V8}
C {devices/switch_ngspice.sym} 20 -80 3 1 {name=S2 model=SW1
device_model=".MODEL SW1 SW 
+ VT=0.7 VH=0.001
+ RON=0.001 ROFF=10G "}
C {devices/lab_pin.sym} 40 -120 1 0 {name=p75 sig_type=std_logic lab=0}
